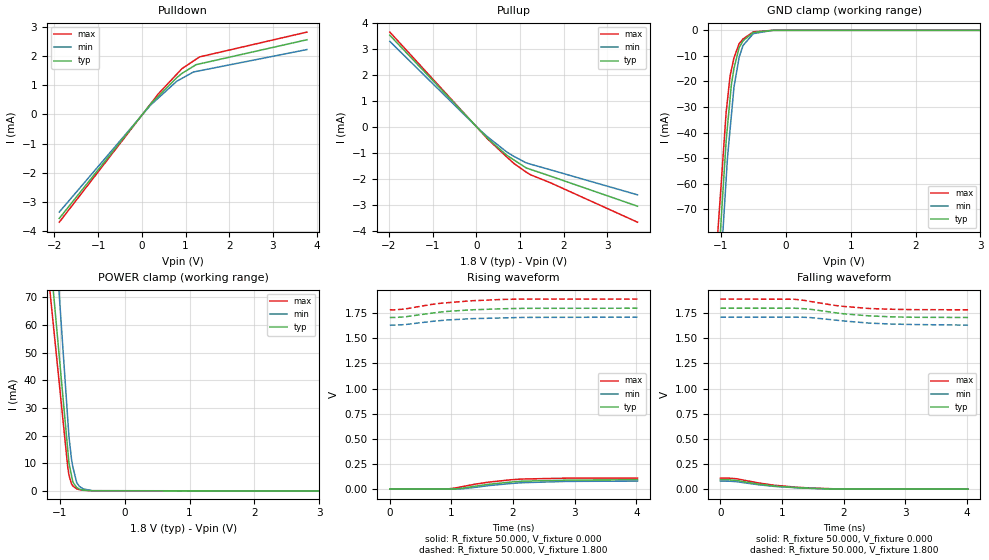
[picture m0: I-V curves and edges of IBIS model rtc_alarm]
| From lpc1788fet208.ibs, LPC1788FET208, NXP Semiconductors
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[Model] rtc_alarm
Model_type Output
Vref=0.00000V
Rref=5.00000Mohms
Cref=10.0000pF
Vmeas=900.000mV
C_comp  436.000fF 415.000fF 457.000fF
| variable typ   min   max
[Voltage Range] 1.8000V 1.71000V 1.89000V
[POWER Clamp Reference] 1.8000V 1.71000V 1.89000V
[Pullup Reference] 1.80000V 1.71000V 1.89000V
[Pulldown Reference] 0.00000V 0.00000V 0.00000V
[GND Clamp Reference] 0.00000V 0.00000V 0.00000V
[Temperature Range]   25   85   -40
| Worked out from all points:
|   slope of the pulldown table from 0 to 0.27 V, typ, clamps not added: 562 ohm
|   slope of the pullup table from 0 to 0.27 V, typ, clamps not added: 568 ohm
|   GND clamp passes 1 mA (typ) near -0.51 V on its own axis
|   POWER clamp passes 1 mA (typ) near -0.72 V on its own axis
|   rising waveform, R_fixture 50.000, V_fixture 0.000: 20-80 % time 782ps typ, 783ps min, 720ps max; typ from 0.001 V to 0.095 V
|   falling waveform, R_fixture 50.000, V_fixture 0.000: 20-80 % time 763ps typ, 784ps min, 782ps max; typ from 0.095 V to 0.001 V
|   rising waveform, R_fixture 50.000, V_fixture 1.800: 20-80 % time 871ps typ, 896ps min, 831ps max; typ from 1.71 V to 1.8 V
|   falling waveform, R_fixture 50.000, V_fixture 1.800: 20-80 % time 814ps typ, 871ps min, 797ps max; typ from 1.8 V to 1.71 V
[GND Clamp]
-1.89V    -432.4mA   -456.1mA   -386mA
-1.71V    -360.2mA   -382.2mA   -320.3mA
-920mV    -43.18mA   -58.23mA   -32.09mA
-900mV    -37.72mA   -50.02mA   -27.38mA
-860mV    -26.81mA   -38.95mA   -17.95mA
-840mV    -21.35mA   -33.41mA   -15.57mA
-800mV    -14.97mA   -22.34mA   -10.8mA
-720mV    -6.806mA   -10.53mA   -5.224mA
-660mV    -4.096mA   -5.926mA   -3.387mA
-500mV    -842uA     -1.282mA   -580.3uA
-200mV    0A         0A         0A
3.78V     0A         0A         0A
[Pulldown]
-1.89V    -3.558mA   -3.34mA    -3.687mA
200mV     354.2uA    321.5uA    361.3uA
380mV     626.3uA    566.7uA    710uA
800mV     1.261mA    1.139mA    1.38mA
920mV     1.408mA    1.238mA    1.571mA
1.18V     1.648mA    1.454mA    1.83mA
1.24V     1.704mA    1.472mA    1.89mA
1.32V     1.731mA    1.495mA    1.97mA
3.78V     2.558mA    2.222mA    2.82mA
[Pullup]
-1.98V    3.52mA     3.284mA    3.642mA
90mV      -146.4uA   -138.9uA   -159uA
260mV     -447.5uA   -390.5uA   -471.2uA
700mV     -1.1mA     -973.7uA   -1.167mA
860mV     -1.275mA   -1.138mA   -1.41mA
1.14V     -1.582mA   -1.387mA   -1.742mA
1.24V     -1.639mA   -1.438mA   -1.845mA
1.68V     -1.888mA   -1.647mA   -2.141mA
3.69V     -3.055mA   -2.618mA   -3.67mA
[POWER Clamp]
-1.98V    299mA      405.5mA    263.6mA
-1.62V    206.1mA    279.6mA    180.3mA
-960mV    35.83mA    53.81mA    27.44mA
-880mV    15.19mA    26.45mA    8.913mA
-860mV    10.03mA    19.61mA    5.665mA
-820mV    5.491mA    11.33mA    2.51mA
-800mV    3.22mA     8.686mA    1.796mA
-740mV    1.203mA    2.969mA    758.4uA
-700mV    685.2uA    1.664mA    453.2uA
-640mV    284.4uA    738.8uA    240.7uA
-500mV    67.68uA    81.7uA     72.6uA
3.69V     0A         0A         0A
[Rising Waveform]
R_fixture = 50.000
V_fixture = 0.000
V_fixture_min = 0.000
V_fixture_max = 0.000
|  time   V(typ)   V(min)   V(max)
0s        920.5uV    1.33mV     1.191mV
940ps     931uV      1.351mV    3.156mV
1.06ns    2.727mV    1.767mV    12.72mV
1.18ns    10.7mV     4.71mV     26.2mV
1.38ns    30.05mV    18.62mV    50.31mV
1.6ns     49.23mV    36.13mV    70.47mV
1.96ns    71.33mV    56.89mV    94.12mV
2.14ns    80.14mV    64.89mV    101.5mV
2.88ns    90.69mV    78.26mV    110.4mV
4.02ns    95.12mV    81.12mV    110.8mV
[Falling Waveform]
R_fixture = 50.000
V_fixture = 0.000
V_fixture_min = 0.000
V_fixture_max = 0.000
|  time   V(typ)   V(min)   V(max)
0s        95.12mV    81.12mV    110.8mV
140ps     93.88mV    80.48mV    110.3mV
260ps     87.71mV    75.41mV    104.7mV
620ps     51.1mV     44.86mV    62.52mV
880ps     31.64mV    28.08mV    39.4mV
1.26ns    15.05mV    14.19mV    19.45mV
1.48ns    8.74mV     8.935mV    11.78mV
1.88ns    1.19mV     1.869mV    3.872mV
2.32ns    920.5uV    1.33mV     1.352mV
4.02ns    920.5uV    1.33mV     1.191mV
[Rising Waveform]
R_fixture = 50.000
V_fixture = 1.800
V_fixture_min = 1.710
V_fixture_max = 1.890
|  time   V(typ)   V(min)   V(max)
0s        1.707V     1.631V     1.783V
80ps      1.707V     1.631V     1.783V
240ps     1.713V     1.636V     1.791V
680ps     1.75V      1.668V     1.837V
820ps     1.761V     1.676V     1.848V
900ps     1.766V     1.681V     1.852V
1.32ns    1.783V     1.695V     1.873V
1.86ns    1.794V     1.703V     1.887V
2.2ns     1.798V     1.708V     1.89V
4.02ns    1.799V     1.71V      1.89V
[Falling Waveform]
R_fixture = 50.000
V_fixture = 1.800
V_fixture_min = 1.710
V_fixture_max = 1.890
|  time   V(typ)   V(min)   V(max)
0s        1.799V     1.71V      1.89V
1.2ns     1.799V     1.71V      1.888V
1.36ns    1.794V     1.709V     1.877V
1.48ns    1.787V     1.705V     1.864V
1.88ns    1.753V     1.68V      1.825V
2.02ns    1.742V     1.671V     1.816V
2.42ns    1.723V     1.651V     1.796V
2.76ns    1.714V     1.642V     1.789V
3.12ns    1.709V     1.637V     1.785V
4.02ns    1.707V     1.631V     1.783V
[Ramp]
dV/dt_r   5.827E-02/8.600E-10   4.569E-02/8.000E-10   6.495E-02/7.800E-10
dV/dt_f   8.700E-02/3.780E-09   7.700E-02/3.780E-09   9.900E-02/3.780E-09
R_load = 50
